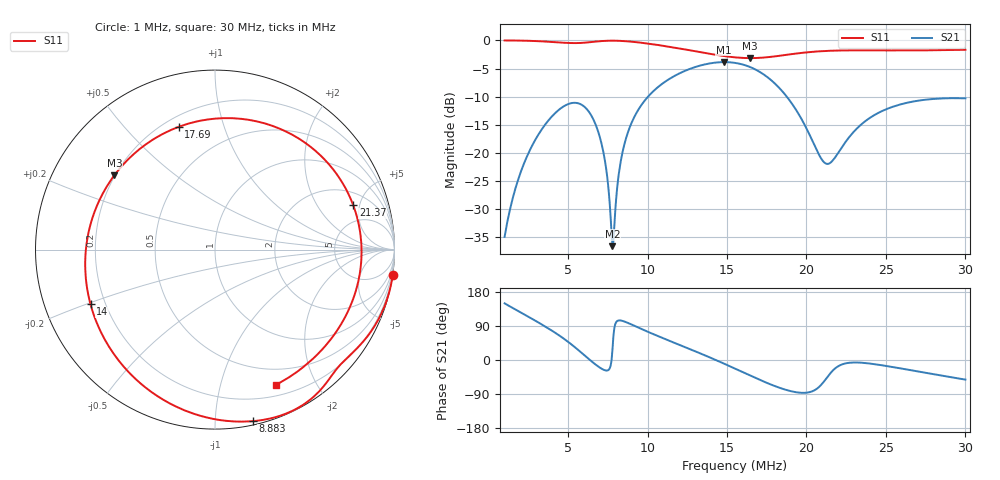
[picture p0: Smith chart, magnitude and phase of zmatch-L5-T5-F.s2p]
# HZ S RI R 50
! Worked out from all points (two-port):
!   505 points, 1 MHz to 30 MHz, reference 50 ohm
!   highest |S21| = -3.85 dB at 14.81 MHz (marker M1); lowest = -36.6 dB at 7.79 MHz (marker M2)
!   |S21| within 3 dB of the highest: 11.37 MHz to 17.68 MHz (6.317 MHz wide, 43.5 % of centre)
!   lowest |S11| = -3.1 dB at 16.42 MHz (marker M3), VSWR 5.60, Z = 9.87 + j15.9 ohm
!   |S11| at or under -10 dB: nowhere
!   S12 and S22 are empty: the file has one direction only
!   S11 on the Smith chart (normalised r, x): 1 MHz: -0, -14; 8.883 MHz: 0.03, -1.24; 14 MHz: 0.14, -0.21; 17.69 MHz: 0.26, +0.72; 21.37 MHz: 3.04, +4.34; 30 MHz: 0.31, -1.50
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1000000  0.991 -0.139  -0.0154 0.00907  0 0  0 0
1920640  0.9619 -0.2658  -0.0376 0.0489  0 0  0 0
3013900  0.8991 -0.4092  -0.0279 0.134  0 0  0 0
4625020  0.7622 -0.5784  0.1298 0.2187  0 0  0 0
5833360  0.6674 -0.6785  0.2534 0.0889  0 0  0 0
7099240  0.5432 -0.8254  0.1113 -0.047  0 0  0 0
7444480  0.49 -0.8652  0.056 -0.0295  0 0  0 0
7789720  0.4292 -0.8992  0.013 0.00703  0 0  0 0
8307580  0.3282 -0.9359  -0.0207 0.0812  0 0  0 0
8882980  0.2096 -0.956  -0.0166 0.169  0 0  0 0
1.066672e7  -0.1705 -0.8954  0.1768 0.3433  0 0  0 0
1.227784e7  -0.4759 -0.6879  0.4339 0.3065  0 0  0 0
1.400404e7  -0.6936 -0.3043  0.6256 0.0569  0 0  0 0
1.48096e7  -0.7233 -0.0739  0.6332 -0.1072  0 0  0 0
1.550008e7  -0.6942 0.1386  0.5831 -0.2439  0 0  0 0
1.642072e7  -0.5602 0.4146  0.4436 -0.3775  0 0  0 0
1.76866e7  -0.2019 0.6841  0.2026 -0.4066  0 0  0 0
1.889494e7  0.2267 0.7156  0.0469 -0.2947  0 0  0 0
2.033344e7  0.6251 0.4863  0.0159 -0.1305  0 0  0 0
2.136916e7  0.7703 0.2468  0.0594 -0.0533  0 0  0 0
2.51668e7  0.7021 -0.4165  0.2386 -0.0719  0 0  0 0
3.000016e7  0.3381 -0.7541  0.1892 -0.24  0 0  0 0
